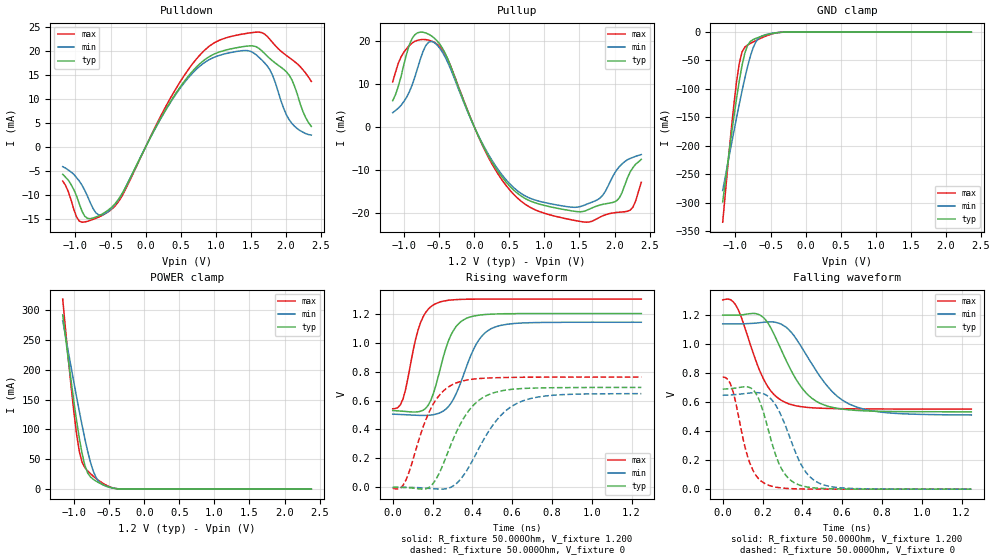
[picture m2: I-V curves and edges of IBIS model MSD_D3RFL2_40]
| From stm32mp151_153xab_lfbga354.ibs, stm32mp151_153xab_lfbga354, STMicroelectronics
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[Model] MSD_D3RFL2_40
Model_type   I/O
C_comp 2.255pF   2.172pF   2.373pF
Vinh = 820.000mV
Vinl = 380.000mV
Vmeas = 600.000mV
Vref = 600.000mV
[Model Spec]
Vinh   820.000mV   790.000mV   870.000mV
Vinl   380.000mV   350.000mV   430.000mV
Vmeas   600.000mV   570.000mV   650.000mV
Vref   600.000mV   570.000mV   650.000mV
[Temperature Range]   25.000   125.000   -40.000
[Voltage Range]   1.200V   1.140V   1.300V
[GND Clamp Reference]   0.00V   0.00V   0.00V
[Pulldown Reference]   0.00V   0.00V   0.00V
[POWER Clamp Reference]   1.200V   1.140V   1.300V
[Pullup Reference]   1.200V   1.140V   1.300V
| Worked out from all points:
|   slope of the pulldown table from 0 to 0.18 V, typ, clamps not added: 35.6 ohm
|   slope of the pullup table from 0 to 0.18 V, typ, clamps not added: 29.6 ohm
|   GND clamp passes 1 mA (typ) near -0.41 V on its own axis
|   POWER clamp passes 1 mA (typ) near -0.41 V on its own axis
|   rising waveform, R_fixture 50.000Ohm, V_fixture 1.200: 20-80 % time 90.2ps typ, 117ps min, 76.1ps max; typ from 0.531 V to 1.2 V
|   rising waveform, R_fixture 50.000Ohm, V_fixture 0: 20-80 % time 149ps typ, 181ps min, 126ps max; typ from 0.001 V to 0.69 V
|   falling waveform, R_fixture 50.000Ohm, V_fixture 1.200: 20-80 % time 159ps typ, 199ps min, 127ps max; typ from 1.2 V to 0.533 V
|   falling waveform, R_fixture 50.000Ohm, V_fixture 0: 20-80 % time 97.4ps typ, 122ps min, 82ps max; typ from 0.69 V to 0 V
[GND Clamp]
-1.182V   -298.7mA   -278.8mA   -334.6mA
-1.064V   -186.5mA   -201.2mA   -176.5mA
-984.9mV  -117.2mA   -151mA     -87.71mA
-945.5mV  -85.9mA    -126.8mA   -54.95mA
-906.1mV  -58.53mA   -103.4mA   -34.88mA
-866.7mV  -37.07mA   -81.25mA   -26.52mA
-827.3mV  -23.31mA   -60.73mA   -22.77mA
-748.5mV  -13.21mA   -27.8mA    -17.44mA
-709.1mV  -11.06mA   -17.22mA   -14.97mA
-630.3mV  -7.606mA   -7.312mA   -10.35mA
-472.7mV  -2.342mA   -2.056mA   -3.037mA
2.364V    24.05nA    406.6nA    2.606nA
[Power Clamp]
-1.164V   291.7mA    282.1mA    318.2mA
-1.085V   217.9mA    230.4mA    219.1mA
-1.006V   147.8mA    179.6mA    130.3mA
-966.7mV  115.3mA    154.7mA    92.57mA
-927.3mV  85.58mA    130.4mA    63.26mA
-887.9mV  59.89mA    107mA      45.2mA
-809.1mV  27.4mA     63.99mA    30.58mA
-730.3mV  16.7mA     30.88mA    21.97mA
-690.9mV  13.64mA    20.08mA    18.15mA
-572.7mV  6.466mA    6.412mA    8.539mA
-336.4mV  182.5uA    350.9uA    204.7uA
2.382V    -20.25nA   -432nA     -2.132nA
[Pulldown]
-1.182V   -5.7mA     -4.1mA     -7.1mA
-945.5mV  -11.88mA   -7.1mA     -15.47mA
-866.7mV  -14.47mA   -9.07mA    -15.65mA
-709.1mV  -14.63mA   -13.73mA   -14.9mA
-551.5mV  -13.38mA   -13.65mA   -13.72mA
-354.6mV  -10.22mA   -10.29mA   -10.71mA
590.9mV   14.46mA    14.13mA    15.79mA
945.5mV   19.18mA    18.53mA    21.44mA
1.379V    20.94mA    20.12mA    23.58mA
1.733V    19.01mA    16.97mA    23.14mA
2.009V    15.7mA     6.71mA     19.11mA
2.364V    4.3mA      2.5mA      13.7mA
[Pullup]
-1.164V   6.1mA      3.309mA    10.46mA
-887.9mV  20.5mA     9.694mA    19.46mA
-730.3mV  21.97mA    17.57mA    20.3mA
-612.1mV  21.14mA    19.84mA    19.93mA
-375.8mV  15.67mA    14.87mA    15.59mA
215.2mV   -7.105mA   -6.743mA   -7.481mA
727.3mV   -16.61mA   -16.01mA   -17.94mA
1.515V    -19.67mA   -18.45mA   -21.93mA
1.791V    -18.12mA   -16.51mA   -20.92mA
1.988V    -17.46mA   -11.09mA   -19.92mA
2.224V    -10.4mA    -7.295mA   -19.28mA
2.382V    -7.5mA     -6.395mA   -12.82mA
[Ramp]
R_load=50.000Ohm
dV/dt_r   407.310mV/120.000ps  383.549mV/149.500ps  452.790mV/101.000ps
dV/dt_f   407.310mV/129.000ps  383.519mV/161.500ps  452.790mV/104.500ps
[Rising waveform]
R_fixture=50.000Ohm
V_fixture=1.200
V_fixture_min=1.140
V_fixture_max=1.300
0s        530.6mV    505.9mV    542.7mV
52ps      525.8mV    502.7mV    612mV
141ps     526.3mV    497.2mV    1.141V
179ps     568.8mV    498mV      1.231V
217ps     705mV      506mV      1.269V
268ps     964.5mV    541.5mV    1.289V
319ps     1.112V     648mV      1.296V
421ps     1.186V     992mV      1.3V
498ps     1.196V     1.098V     1.3V
1.249ns   1.2V       1.14V      1.3V
[Rising waveform]
R_fixture=50.000Ohm
V_fixture=0
0s        873.9uV    858uV      -5.749mV
64ps      -93.44uV   771.7uV    43.92mV
192ps     10.23mV    -7.297mV   545.8mV
307ps     343.4mV    13.58mV    714mV
370ps     506.9mV    112.1mV    740.5mV
434ps     602.6mV    272.5mV    751.5mV
536ps     663.9mV    486.9mV    757.8mV
626ps     680.5mV    581.7mV    760.1mV
804ps     688.2mV    636.2mV    761.4mV
1.249ns   690.4mV    647.4mV    761.5mV
[Falling waveform]
R_fixture=50.000Ohm
V_fixture=1.200
V_fixture_min=1.140
V_fixture_max=1.300
0s        1.2V       1.139V     1.304V
77ps      1.2V       1.139V     1.24V
192ps     1.196V     1.148V     797.1mV
243ps     1.108V     1.153V     674.9mV
319ps     886.2mV    1.116V     595.2mV
447ps     627.5mV    865.2mV    561mV
549ps     564.3mV    674.1mV    555.7mV
638ps     546.3mV    584.9mV    553.8mV
817ps     535.9mV    527.8mV    552.4mV
1.249ns   533mV      511.1mV    552.2mV
[Falling waveform]
R_fixture=50.000Ohm
V_fixture=0
0s        689.8mV    647.5mV    772mV
52ps      694.5mV    650.5mV    672.5mV
141ps     697.6mV    663.3mV    162.9mV
179ps     628.4mV    664.7mV    74.16mV
217ps     470.3mV    650mV      34.96mV
268ps     227.2mV    574.9mV    13.54mV
319ps     92.19mV    423.2mV    5.501mV
396ps     23.82mV    164.3mV    1.426mV
485ps     6.144mV    40.92mV    291uV
1.249ns   1.494uV    17.97uV    0V
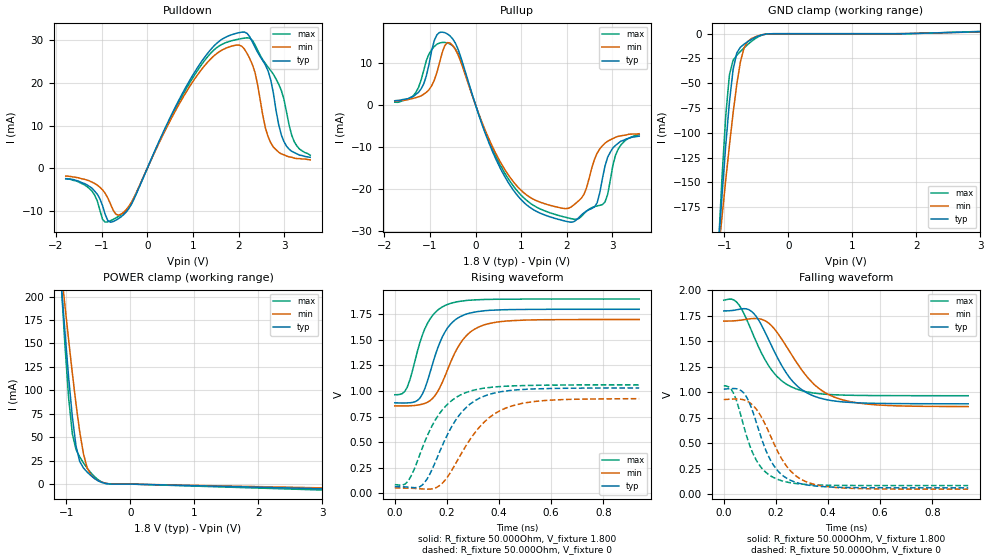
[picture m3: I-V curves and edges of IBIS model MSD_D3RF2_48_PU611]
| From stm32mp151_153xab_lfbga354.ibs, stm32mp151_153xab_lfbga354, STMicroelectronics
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[Model] MSD_D3RF2_48_PU611
Model_type   I/O
C_comp 2.420pF   2.338pF   2.542pF
Vinh = 1.150V
Vinl = 650.000mV
Vmeas = 900.000mV
Vref = 900.000mV
[Model Spec]
Vinh   1.150V   1.100V   1.200V
Vinl   650.000mV   600.000mV   700.000mV
Vmeas   900.000mV   850.000mV   950.000mV
Vref   900.000mV   850.000mV   950.000mV
[Temperature Range]   25.000   125.000   -40.000
[Voltage Range]   1.800V   1.700V   1.900V
[GND Clamp Reference]   0.00V   0.00V   0.00V
[Pulldown Reference]   0.00V   0.00V   0.00V
[POWER Clamp Reference]   1.800V   1.700V   1.900V
[Pullup Reference]   1.800V   1.700V   1.900V
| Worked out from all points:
|   slope of the pulldown table from 0 to 0.27 V, typ, clamps not added: 41 ohm
|   slope of the pullup table from 0 to 0.27 V, typ, clamps not added: 32.3 ohm
|   GND clamp passes 1 mA (typ) near -0.40 V on its own axis
|   POWER clamp passes 1 mA (typ) near -0.41 V on its own axis
|   rising waveform, R_fixture 50.000Ohm, V_fixture 1.800: 20-80 % time 80.9ps typ, 100ps min, 74.8ps max; typ from 0.885 V to 1.8 V
|   rising waveform, R_fixture 50.000Ohm, V_fixture 0: 20-80 % time 126ps typ, 149ps min, 119ps max; typ from 0.065 V to 1.03 V
|   falling waveform, R_fixture 50.000Ohm, V_fixture 1.800: 20-80 % time 126ps typ, 151ps min, 117ps max; typ from 1.8 V to 0.888 V
|   falling waveform, R_fixture 50.000Ohm, V_fixture 0: 20-80 % time 91.7ps typ, 112ps min, 83.3ps max; typ from 1.03 V to 0.064 V
[GND Clamp]
-1.785V   -902.7mA   -689.9mA   -1.212A
-1.094V   -215.4mA   -221.4mA   -216.2mA
-1.036V   -162.5mA   -184.1mA   -144.1mA
-978.8mV  -112.8mA   -147.7mA   -82.76mA
-921.2mV  -69mA      -112.8mA   -41.61mA
-863.6mV  -36.18mA   -79.97mA   -26.74mA
-806.1mV  -19.38mA   -50.93mA   -21.76mA
-748.5mV  -13.55mA   -28.08mA   -17.89mA
-690.9mV  -10.49mA   -14.02mA   -14.25mA
-575.8mV  -5.695mA   -4.879mA   -7.699mA
-287.9mV  -74.99uA   -123uA     -60.99uA
3.57V     2.964mA    2.553mA    3.541mA
[Power Clamp]
-1.77V    884.1mA    691.2mA    1.161A
-1.079V   213.1mA    227.1mA    213mA
-1.021V   161.6mA    189.9mA    147.5mA
-963.6mV  113.5mA    153.4mA    91.69mA
-906.1mV  71.69mA    118.2mA    53.58mA
-848.5mV  40.49mA    85.18mA    36.76mA
-790.9mV  24.18mA    55.77mA    28.99mA
-733.3mV  17.31mA    32.52mA    22.74mA
-618.2mV  9.175mA    9.93mA     12.21mA
-503mV    3.531mA    3.626mA    4.592mA
-330.3mV  169.7uA    350.8uA    198.1uA
3.585V    -5.947mA   -4.827mA   -7.552mA
[Pulldown]
-1.785V   -2.4mA     -1.8mA     -2.4mA
-1.209V   -4.6mA     -3.2mA     -5.3mA
-921.2mV  -10.71mA   -5.8mA     -12.53mA
-690.9mV  -12.11mA   -10.65mA   -11.59mA
-518.2mV  -10.81mA   -10.23mA   -10.36mA
1.094V    23.43mA    21.74mA    22.76mA
2.073V    31.84mA    28.54mA    30.34mA
2.361V    28.33mA    22.42mA    28.91mA
2.706V    20.69mA    6mA        22.85mA
2.994V    6.3mA      3.2mA      16.2mA
3.224V    3.7mA      2.4mA      6.2mA
3.57V     2.6mA      2mA        3.1mA
[Pullup]
-1.77V    1mA        973.7uA    673.7uA
-1.309V   2.5mA      1.747mA    2.963mA
-1.021V   9.6mA      3.616mA    12.09mA
-848.5mV  16.65mA    7.666mA    14.42mA
-618.2mV  16.89mA    14.82mA    14.74mA
763.6mV   -19.21mA   -17.32mA   -18.28mA
2.088V    -27.84mA   -24.27mA   -26.98mA
2.376V    -25.6mA    -21.22mA   -25.8mA
2.606V    -24.21mA   -12.89mA   -24.14mA
2.779V    -17.5mA    -9.684mA   -23.66mA
3.124V    -9.1mA     -7.453mA   -10.51mA
3.585V    -7.4mA     -6.826mA   -7.047mA
[Ramp]
R_load=50.000Ohm
dV/dt_r   563.493mV/104.500ps  514.551mV/125.500ps  571.944mV/97.000ps
dV/dt_f   563.493mV/109.000ps  514.551mV/132.000ps  571.944mV/101.000ps
[Rising waveform]
R_fixture=50.000Ohm
V_fixture=1.800
V_fixture_min=1.700
V_fixture_max=1.900
0s        884.7mV    855.2mV    963.7mV
29ps      883.2mV    854.3mV    975.4mV
48ps      883.7mV    854.9mV    1.039V
96ps      929.5mV    866.1mV    1.471V
115ps     1.022V     879.1mV    1.607V
154ps     1.34V      954.3mV    1.766V
202ps     1.616V     1.205V     1.847V
269ps     1.748V     1.526V     1.884V
355ps     1.788V     1.656V     1.896V
938ps     1.8V       1.7V       1.9V
[Rising waveform]
R_fixture=50.000Ohm
V_fixture=0
0s        64.78mV    51.61mV    84.22mV
48ps      60.37mV    49.89mV    109.8mV
115ps     106.3mV    40.91mV    503.3mV
183ps     469.6mV    99.37mV    817.2mV
230ps     700.8mV    273.6mV    928.3mV
269ps     826.1mV    446.7mV    981.2mV
355ps     960.8mV    723.1mV    1.032V
451ps     1.008V     855.2mV    1.05V
614ps     1.026V     913.1mV    1.058V
938ps     1.03V      925.2mV    1.06V
[Falling waveform]
R_fixture=50.000Ohm
V_fixture=1.800
V_fixture_min=1.700
V_fixture_max=1.900
0s        1.799V     1.699V     1.904V
29ps      1.802V     1.7V       1.915V
58ps      1.814V     1.706V     1.859V
115ps     1.774V     1.724V     1.552V
154ps     1.613V     1.708V     1.34V
192ps     1.411V     1.629V     1.192V
278ps     1.072V     1.299V     1.034V
365ps     946.9mV    1.039V     987.7mV
460ps     906mV      924.2mV    973.4mV
938ps     888.1mV    861.2mV    967.4mV
[Falling waveform]
R_fixture=50.000Ohm
V_fixture=0
0s        1.032V     929.8mV    1.065V
20ps      1.036V     932.8mV    1.052V
39ps      1.038V     935.1mV    983.9mV
87ps      956.2mV    917.7mV    576.4mV
135ps     623.7mV    798.6mV    293.2mV
163ps     422.7mV    665.5mV    212.8mV
202ps     247.6mV    445.9mV    152.4mV
259ps     135mV      222.4mV    112.9mV
355ps     81.42mV    93.96mV    92.49mV
938ps     64.28mV    51.3mV     86.62mV
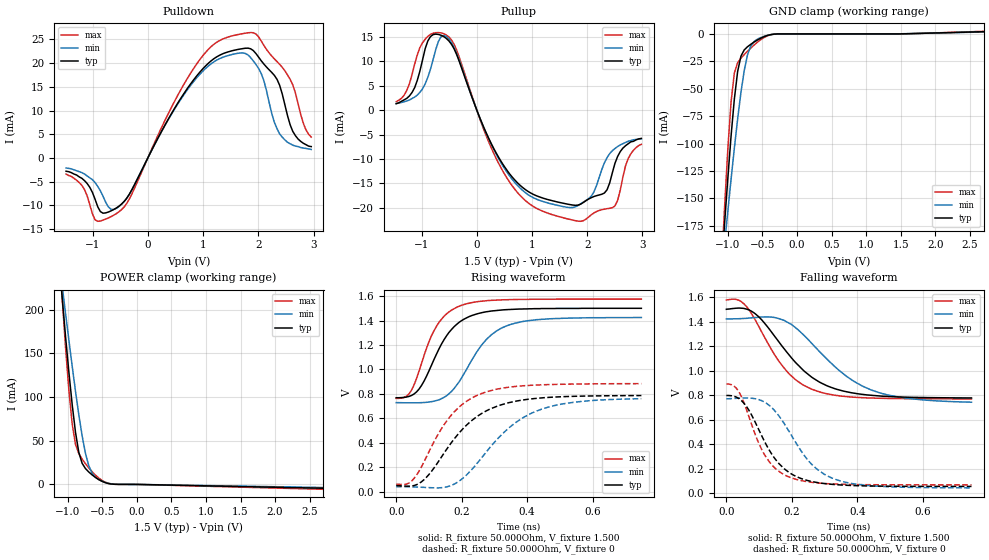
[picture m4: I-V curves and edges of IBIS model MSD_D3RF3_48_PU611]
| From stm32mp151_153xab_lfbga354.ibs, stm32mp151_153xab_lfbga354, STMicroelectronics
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[Model] MSD_D3RF3_48_PU611
Model_type   I/O
C_comp 2.434pF   2.351pF   2.557pF
Vinh = 925.000mV
Vinl = 575.000mV
Vmeas = 750.000mV
Vref = 750.000mV
[Model Spec]
Vinh   925.000mV   888.000mV   963.000mV
Vinl   575.000mV   538.000mV   613.000mV
Vmeas   750.000mV   713.000mV   788.000mV
Vref   750.000mV   713.000mV   788.000mV
[Temperature Range]   25.000   125.000   -40.000
[Voltage Range]   1.500V   1.425V   1.575V
[GND Clamp Reference]   0.00V   0.00V   0.00V
[Pulldown Reference]   0.00V   0.00V   0.00V
[POWER Clamp Reference]   1.500V   1.425V   1.575V
[Pullup Reference]   1.500V   1.425V   1.575V
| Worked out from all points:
|   slope of the pulldown table from 0 to 0.225 V, typ, clamps not added: 44.1 ohm
|   slope of the pullup table from 0 to 0.225 V, typ, clamps not added: 37.5 ohm
|   GND clamp passes 1 mA (typ) near -0.40 V on its own axis
|   POWER clamp passes 1 mA (typ) near -0.41 V on its own axis
|   rising waveform, R_fixture 50.000Ohm, V_fixture 1.500: 20-80 % time 91.6ps typ, 108ps min, 76.8ps max; typ from 0.769 V to 1.5 V
|   rising waveform, R_fixture 50.000Ohm, V_fixture 0: 20-80 % time 144ps typ, 163ps min, 123ps max; typ from 0.051 V to 0.787 V
|   falling waveform, R_fixture 50.000Ohm, V_fixture 1.500: 20-80 % time 149ps typ, 175ps min, 121ps max; typ from 1.5 V to 0.778 V
|   falling waveform, R_fixture 50.000Ohm, V_fixture 0: 20-80 % time 100ps typ, 118ps min, 83.1ps max; typ from 0.798 V to 0.055 V
[GND Clamp]
-1.48V    -595mA     -480.6mA   -764.6mA
-1.098V   -218.9mA   -223.9mA   -221.2mA
-1.05V    -174.8mA   -192.9mA   -160.5mA
-1.002V   -132.5mA   -162.4mA   -106.1mA
-954.6mV  -93.38mA   -132.8mA   -62.24mA
-906.8mV  -59.5mA    -104.2mA   -35.79mA
-859.1mV  -34.24mA   -77.51mA   -26.21mA
-811.4mV  -20.29mA   -53.38mA   -22.14mA
-715.9mV  -11.7mA    -18.98mA   -15.79mA
-572.7mV  -5.58mA    -4.768mA   -7.539mA
-286.4mV  -69.81uA   -117.8uA   -56.41uA
2.959V    2.404mA    2.05mA     2.9mA
[Power Clamp]
-1.459V   578.8mA    480.2mA    724.4mA
-1.077V   211.7mA    226.1mA    211.2mA
-1.03V    168.8mA    195.2mA    156.4mA
-981.8mV  128.2mA    164.8mA    107.5mA
-934.1mV  91.06mA    135.1mA    68.98mA
-886.4mV  59.53mA    106.6mA    45.83mA
-838.6mV  36.63mA    79.81mA    35.19mA
-743.2mV  18.22mA    35.86mA    23.75mA
-647.7mV  11mA       13.06mA    14.65mA
-552.3mV  5.639mA    5.582mA    7.423mA
-313.6mV  109.4uA    249.9uA    123.7uA
2.98V     -4.843mA   -3.907mA   -6.18mA
[Pulldown]
-1.48V    -2.8mA     -2.1mA     -3.4mA
-1.193V   -4.3mA     -3.1mA     -5.8mA
-954.6mV  -8.73mA    -5.2mA     -13.05mA
-811.4mV  -11.65mA   -8.07mA    -13.11mA
-525mV    -10.19mA   -10.28mA   -11.37mA
906.8mV   17.61mA    17.2mA     20.19mA
1.766V    23.14mA    22.04mA    26.32mA
2.052V    20.52mA    17.86mA    24.7mA
2.386V    15.36mA    5.1mA      19.76mA
2.625V    5.6mA      2.7mA      15.4mA
2.816V    3.1mA      2.1mA      7.3mA
2.959V    2.4mA      1.8mA      4.4mA
[Pullup]
-1.459V   1.3mA      1.357mA    1.729mA
-1.173V   3.6mA      2.371mA    7.243mA
-981.8mV  10.3mA     4.357mA    13.82mA
-838.6mV  15.06mA    8.371mA    15.51mA
-552.3mV  14.69mA    15.08mA    15.38mA
640.9mV   -13.72mA   -14.19mA   -15.51mA
1.834V    -19.47mA   -19.55mA   -22.76mA
2.12V     -17.71mA   -16.78mA   -21.08mA
2.311V    -16.99mA   -10.81mA   -20.29mA
2.502V    -10.9mA    -7.871mA   -19.63mA
2.741V    -6.9mA     -6.386mA   -9.928mA
2.98V     -5.8mA     -5.9mA     -7.014mA
[Ramp]
R_load=50.000Ohm
dV/dt_r   437.283mV/118.500ps  423.876mV/137.000ps  486.861mV/101.000ps
dV/dt_f   437.283mV/125.000ps  423.846mV/149.000ps  486.861mV/103.000ps
[Rising waveform]
R_fixture=50.000Ohm
V_fixture=1.500
V_fixture_min=1.425
V_fixture_max=1.575
0s        769mV      729.4mV    763.4mV
39ps      779.7mV    727.4mV    800.5mV
69ps      837.3mV    728mV      980.1mV
100ps     987.8mV    734.3mV    1.226V
123ps     1.125V     746.4mV    1.353V
154ps     1.276V     785.1mV    1.455V
192ps     1.385V     898.2mV    1.517V
276ps     1.472V     1.247V     1.562V
345ps     1.49V      1.364V     1.571V
749ps     1.5V       1.425V     1.575V
[Rising waveform]
R_fixture=50.000Ohm
V_fixture=0
0s        51.41mV    42.64mV    63.72mV
46ps      47.29mV    40.53mV    85.37mV
85ps      99.46mV    36.41mV    245mV
131ps     255.4mV    32.43mV    484mV
169ps     403.7mV    52.98mV    629.1mV
253ps     626.5mV    251.9mV    795.4mV
345ps     729.3mV    524mV      855.6mV
444ps     767.6mV    675.6mV    874.6mV
544ps     780.7mV    732.6mV    880.8mV
749ps     786.9mV    760.9mV    884.4mV
[Falling waveform]
R_fixture=50.000Ohm
V_fixture=1.500
V_fixture_min=1.425
V_fixture_max=1.575
0s        1.503V     1.424V     1.579V
46ps      1.512V     1.427V     1.565V
85ps      1.473V     1.435V     1.432V
138ps     1.317V     1.439V     1.173V
184ps     1.155V     1.401V     998.3mV
261ps     947.4mV    1.224V     849.7mV
368ps     828.3mV    953.4mV    788.7mV
444ps     799.6mV    842.1mV    777.2mV
552ps     784.3mV    775.3mV    772.2mV
749ps     778.1mV    743.4mV    770.3mV
[Falling waveform]
R_fixture=50.000Ohm
V_fixture=0
0s        798.3mV    770.5mV    892mV
39ps      772.3mV    776.3mV    825.3mV
69ps      677.4mV    777.6mV    625.8mV
115ps     431.1mV    746.4mV    321.7mV
154ps     262.6mV    654.2mV    191.7mV
192ps     168.4mV    502.9mV    131.5mV
261ps     94.89mV    235.1mV    88.27mV
337ps     68.77mV    108.8mV    73.69mV
467ps     57.1mV     55.89mV    68.26mV
749ps     54.62mV    42.96mV    67.42mV
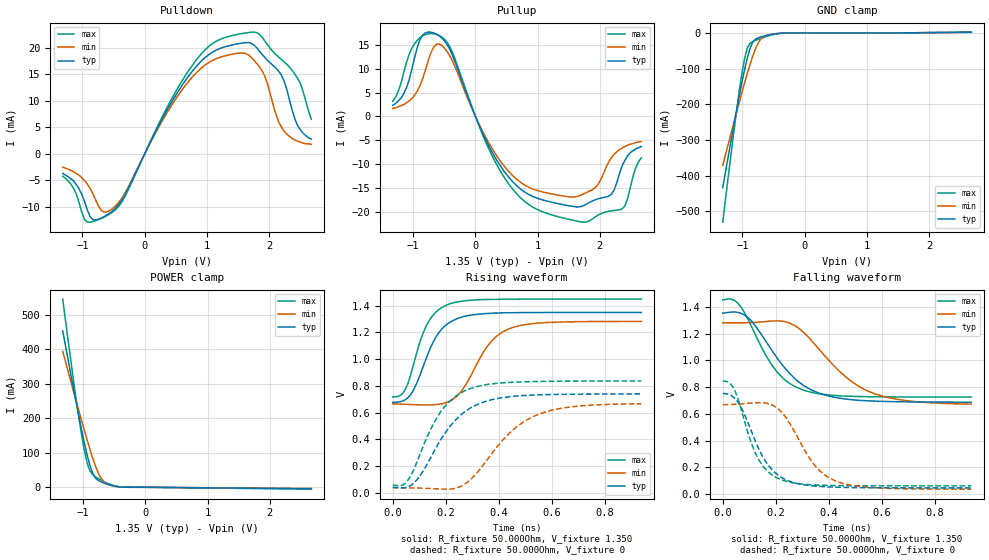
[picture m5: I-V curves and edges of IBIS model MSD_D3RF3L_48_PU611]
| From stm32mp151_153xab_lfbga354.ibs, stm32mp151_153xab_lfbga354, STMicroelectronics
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[Model] MSD_D3RF3L_48_PU611
Model_type   I/O
C_comp 2.442pF   2.357pF   2.567pF
Vinh = 810.000mV
Vinl = 540.000mV
Vmeas = 675.000mV
Vref = 675.000mV
[Model Spec]
Vinh   810.000mV   777.000mV   860.000mV
Vinl   540.000mV   507.000mV   590.000mV
Vmeas   675.000mV   642.000mV   725.000mV
Vref   675.000mV   642.000mV   725.000mV
[Temperature Range]   25.000   125.000   -40.000
[Voltage Range]   1.350V   1.283V   1.450V
[GND Clamp Reference]   0.00V   0.00V   0.00V
[Pulldown Reference]   0.00V   0.00V   0.00V
[POWER Clamp Reference]   1.350V   1.283V   1.450V
[Pullup Reference]   1.350V   1.283V   1.450V
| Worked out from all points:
|   slope of the pulldown table from 0 to 0.203 V, typ, clamps not added: 42.2 ohm
|   slope of the pullup table from 0 to 0.203 V, typ, clamps not added: 34.5 ohm
|   GND clamp passes 1 mA (typ) near -0.40 V on its own axis
|   POWER clamp passes 1 mA (typ) near -0.41 V on its own axis
|   rising waveform, R_fixture 50.000Ohm, V_fixture 1.350: 20-80 % time 92.2ps typ, 115ps min, 77.8ps max; typ from 0.677 V to 1.35 V
|   rising waveform, R_fixture 50.000Ohm, V_fixture 0: 20-80 % time 147ps typ, 178ps min, 125ps max; typ from 0.043 V to 0.741 V
|   falling waveform, R_fixture 50.000Ohm, V_fixture 1.350: 20-80 % time 163ps typ, 195ps min, 130ps max; typ from 1.35 V to 0.688 V
|   falling waveform, R_fixture 50.000Ohm, V_fixture 0: 20-80 % time 105ps typ, 124ps min, 87.4ps max; typ from 0.753 V to 0.047 V
[GND Clamp]
-1.318V   -433.7mA   -371.1mA   -530mA
-1.142V   -261.4mA   -253.3mA   -281.2mA
-1.055V   -178.9mA   -195.8mA   -166mA
-1.011V   -139.7mA   -167.7mA   -114.9mA
-966.7mV  -102.9mA   -140.2mA   -71.99mA
-922.7mV  -70.02mA   -113.6mA   -42.32mA
-878.8mV  -43.37mA   -88.29mA   -28.9mA
-790.9mV  -17.22mA   -44.18mA   -20.7mA
-703mV    -11.06mA   -16.21mA   -14.99mA
-527.3mV  -4.011mA   -3.391mA   -5.355mA
-307.6mV  -127.4uA   -187.4uA   -115uA
2.68V     2.164mA    1.839mA    2.56mA
[Power Clamp]
-1.33V    453.1mA    393.6mA    545.2mA
-1.111V   242.6mA    247.9mA    251.6mA
-1.023V   162.8mA    190.9mA    148.7mA
-978.8mV  125.7mA    162.9mA    104.2mA
-934.9mV  91.62mA    135.6mA    68.68mA
-890.9mV  62.22mA    109.2mA    47.04mA
-847mV    39.86mA    84.29mA    36.52mA
-803mV    26.49mA    61.46mA    30.42mA
-715.1mV  15.8mA     26.67mA    20.89mA
-671.2mV  12.56mA    16.56mA    16.71mA
-407.6mV  931.1uA    1.216mA    1.127mA
2.668V    -4.266mA   -3.419mA   -5.488mA
[Pulldown]
-1.318V   -3.7mA     -2.5mA     -4.2mA
-1.098V   -5.8mA     -3.7mA     -7.6mA
-922.7mV  -10.54mA   -5.7mA     -12.83mA
-703mV    -12.11mA   -10.54mA   -12.17mA
-483.3mV  -10.4mA    -9.969mA   -10.65mA
790.9mV   15.91mA    14.77mA    17.06mA
1.582V    20.87mA    18.98mA    22.68mA
1.889V    18.72mA    15.63mA    21.96mA
2.197V    14.84mA    5.1mA      17.77mA
2.329V    10.1mA     3.3mA      16.32mA
2.461V    5.3mA      2.4mA      14.2mA
2.68V     2.8mA      1.8mA      6.5mA
[Pullup]
-1.33V    2.3mA      1.652mA    3.135mA
-1.023V   9.8mA      3.715mA    14.27mA
-890.9mV  16.11mA    6.472mA    16.51mA
-715.1mV  17.65mA    13.35mA    17.35mA
-451.5mV  14.98mA    13.53mA    15.46mA
295.4mV   -8.126mA   -7.329mA   -8.964mA
910.6mV   -16.72mA   -15.17mA   -18.95mA
1.702V    -18.93mA   -16.49mA   -22.14mA
1.965V    -17.33mA   -14.42mA   -20.77mA
2.185V    -16.37mA   -8.694mA   -19.82mA
2.361V    -10.3mA    -6.643mA   -19.39mA
2.668V    -6.3mA     -5.3mA     -8.693mA
[Ramp]
R_load=50.000Ohm
dV/dt_r   407.025mV/120.000ps  374.118mV/149.000ps  449.694mV/102.000ps
dV/dt_f   407.025mV/134.500ps  374.058mV/162.000ps  449.694mV/109.000ps
[Rising waveform]
R_fixture=50.000Ohm
V_fixture=1.350
V_fixture_min=1.283
V_fixture_max=1.450
0s        677.4mV    665.9mV    718.5mV
39ps      688.6mV    663.4mV    747.5mV
68ps      736.1mV    661.2mV    884.2mV
125ps     999.5mV    658.2mV    1.243V
163ps     1.165V     660.9mV    1.353V
202ps     1.257V     675.6mV    1.404V
259ps     1.314V     760.6mV    1.434V
365ps     1.343V     1.117V     1.447V
432ps     1.347V     1.222V     1.449V
938ps     1.35V      1.283V     1.45V
[Rising waveform]
R_fixture=50.000Ohm
V_fixture=0
0s        42.68mV    37.92mV    58.75mV
48ps      40.35mV    37.89mV    72.84mV
87ps      88.5mV     37.09mV    208.7mV
135ps     233.2mV    34.13mV    441.6mV
183ps     403.7mV    29.26mV    612.1mV
278ps     615.8mV    74.7mV     768.8mV
441ps     719.8mV    448.8mV    826.8mV
527ps     731.9mV    568.3mV    832.8mV
662ps     738mV      641.1mV    836.3mV
938ps     740.7mV    667.3mV    837.3mV
[Falling waveform]
R_fixture=50.000Ohm
V_fixture=1.350
V_fixture_min=1.283
V_fixture_max=1.450
0s        1.354V     1.282V     1.453V
48ps      1.362V     1.282V     1.444V
96ps      1.319V     1.283V     1.306V
154ps     1.17V      1.289V     1.07V
202ps     1.028V     1.296V     922.4mV
298ps     823.3mV    1.223V     782.9mV
441ps     718.1mV    917.7mV    735.6mV
547ps     698.4mV    771.9mV    729.2mV
700ps     690.3mV    698.1mV    726.9mV
938ps     687.9mV    673.5mV    726.2mV
[Falling waveform]
R_fixture=50.000Ohm
V_fixture=0
0s        752.5mV    669.9mV    845mV
29ps      741.6mV    671.2mV    826.5mV
48ps      712.2mV    672.8mV    764.3mV
106ps     481.8mV    681.1mV    393.7mV
135ps     343.7mV    684.1mV    261.3mV
211ps     139.6mV    635.2mV    116.5mV
345ps     61.28mV    221.5mV    69.32mV
422ps     52.48mV    102.2mV    64.68mV
566ps     48.02mV    49.22mV    62.96mV
938ps     47.18mV    37.63mV    62.61mV
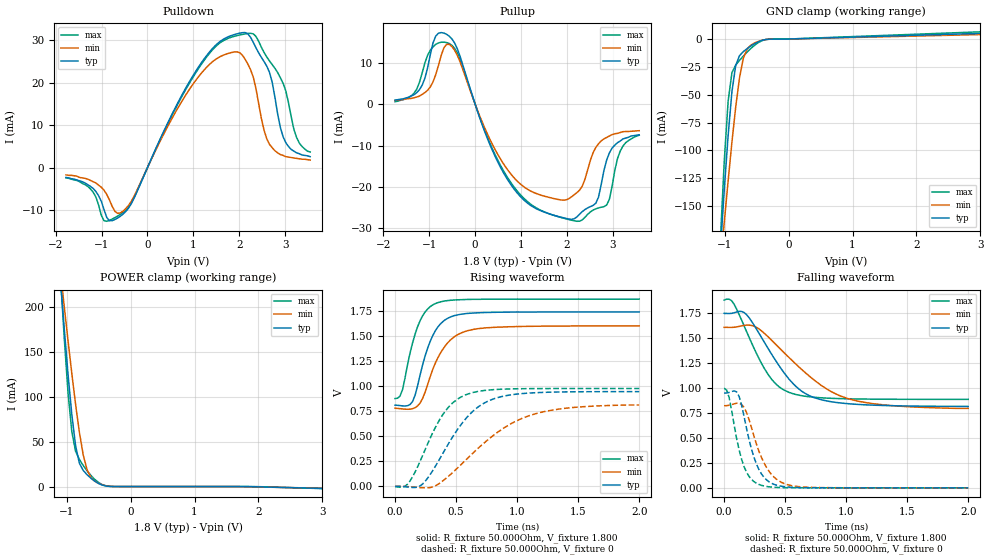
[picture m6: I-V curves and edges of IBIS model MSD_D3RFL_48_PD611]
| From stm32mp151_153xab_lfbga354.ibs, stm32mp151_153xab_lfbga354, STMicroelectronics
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[Model] MSD_D3RFL_48_PD611
Model_type   I/O
C_comp 2.419pF   2.335pF   2.543pF
Vinh = 1.440V
Vinl = 360.000mV
Vmeas = 900.000mV
Vref = 900.000mV
[Model Spec]
Vinh   1.440V   1.365V   1.515V
Vinl   360.000mV   285.000mV   435.000mV
Vmeas   900.000mV   825.000mV   975.000mV
Vref   900.000mV   825.000mV   975.000mV
[Temperature Range]   25.000   125.000   -40.000
[Voltage Range]   1.800V   1.650V   1.950V
[GND Clamp Reference]   0.00V   0.00V   0.00V
[Pulldown Reference]   0.00V   0.00V   0.00V
[POWER Clamp Reference]   1.800V   1.650V   1.950V
[Pullup Reference]   1.800V   1.650V   1.950V
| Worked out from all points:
|   slope of the pulldown table from 0 to 0.27 V, typ, clamps not added: 41 ohm
|   slope of the pullup table from 0 to 0.27 V, typ, clamps not added: 32.3 ohm
|   GND clamp passes 1 mA (typ) near -0.40 V on its own axis
|   POWER clamp passes 1 mA (typ) near -0.41 V on its own axis
|   rising waveform, R_fixture 50.000Ohm, V_fixture 1.800: 20-80 % time 148ps typ, 188ps min, 132ps max; typ from 0.813 V to 1.75 V
|   rising waveform, R_fixture 50.000Ohm, V_fixture 0: 20-80 % time 320ps typ, 495ps min, 248ps max; typ from 0.001 V to 0.948 V
|   falling waveform, R_fixture 50.000Ohm, V_fixture 1.800: 20-80 % time 322ps typ, 470ps min, 248ps max; typ from 1.75 V to 0.814 V
|   falling waveform, R_fixture 50.000Ohm, V_fixture 0: 20-80 % time 127ps typ, 158ps min, 110ps max; typ from 0.947 V to 0 V
[GND Clamp]
-1.773V   -890.5mA   -681.7mA   -1.194A
-1.064V   -187.2mA   -201.7mA   -177.4mA
-1.005V   -134.5mA   -163.9mA   -108.4mA
-945.5mV  -86.45mA   -127.3mA   -55.67mA
-886.4mV  -47.42mA   -92.59mA   -30.32mA
-827.3mV  -23.74mA   -61.09mA   -23.33mA
-768.2mV  -14.98mA   -35.02mA   -19.18mA
-709.1mV  -11.37mA   -17.47mA   -15.38mA
-650mV    -8.667mA   -9.004mA   -11.8mA
-531.8mV  -4.168mA   -3.528mA   -5.57mA
-295.4mV  -94.96uA   -150.6uA   -80.9uA
3.545V    5.967mA    4.73mA     7.643mA
[Power Clamp]
-1.745V   860.1mA    674.5mA    1.127A
-1.095V   228.4mA    237.9mA    233.3mA
-1.036V   174.8mA    199.6mA    164.2mA
-977.3mV  124.4mA    162mA      104mA
-918.2mV  79.78mA    125.5mA    60.72mA
-859.1mV  45.15mA    91.12mA    39.2mA
-800mV    25.86mA    60.27mA    30.1mA
-740.9mV  17.99mA    35.42mA    23.53mA
-681.8mV  13.28mA    19.02mA    17.73mA
-504.5mV  3.581mA    3.685mA    4.694mA
-268.2mV  27.02uA    97.66uA    31.41uA
3.573V    -3.02mA    -2.625mA   -3.524mA
[Pulldown]
-1.773V   -2.3mA     -1.7mA     -2.4mA
-1.241V   -4.4mA     -3mA       -5mA
-945.5mV  -9.88mA    -5.3mA     -12.48mA
-531.8mV  -10.94mA   -10.24mA   -10.54mA
1.064V    22.92mA    20.76mA    22.58mA
1.595V    29.86mA    26.24mA    29.55mA
2.068V    31.83mA    26.53mA    31.41mA
2.305V    29.56mA    21.37mA    31.55mA
2.659V    22.45mA    5.5mA      25.16mA
3.014V    5.9mA      2.6mA      18.1mA
3.25V     3.5mA      2.2mA      7.1mA
3.545V    2.6mA      1.8mA      3.7mA
[Pullup]
-1.745V   1mA        900uA      600uA
-1.332V   2.3mA      1.562mA    2.669mA
-1.036V   8.8mA      3.377mA    11.85mA
-859.1mV  16.48mA    7.15mA     14.48mA
-622.7mV  16.92mA    14.48mA    14.91mA
-386.4mV  13.35mA    11.77mA    12.34mA
795.5mV   -19.73mA   -17.13mA   -19.24mA
2.214V    -27.27mA   -21.39mA   -28.32mA
2.745V    -19.44mA   -8.877mA   -24.91mA
2.982V    -10.6mA    -7.338mA   -19.91mA
3.159V    -8.9mA     -6.838mA   -11.35mA
3.573V    -7.4mA     -6.4mA     -7.508mA
[Ramp]
R_load=50.000Ohm
dV/dt_r   564.000mV/234.500ps  490.979mV/343.000ps  590.250mV/189.500ps
dV/dt_f   563.968mV/225.000ps  490.014mV/315.000ps  590.250mV/179.000ps
[Rising waveform]
R_fixture=50.000Ohm
V_fixture=1.800
V_fixture_min=1.650
V_fixture_max=1.950
0s        813.2mV    782mV      878.5mV
41ps      808.5mV    777.6mV    904.3mV
62ps      805.5mV    774.9mV    970.9mV
143ps     848mV      777.3mV    1.433V
225ps     1.212V     878.4mV    1.705V
266ps     1.379V     1.016V     1.773V
327ps     1.55V      1.225V     1.827V
470ps     1.702V     1.482V     1.863V
654ps     1.735V     1.573V     1.871V
2ns       1.745V     1.606V     1.873V
[Rising waveform]
R_fixture=50.000Ohm
V_fixture=0
0s        1.048mV    1.221mV    -2.543mV
103ps     -5.794mV   -1.842mV   23.8mV
225ps     23.65mV    -13.02mV   307.5mV
388ps     323.2mV    52.22mV    712.6mV
470ps     491.9mV    137.1mV    833.8mV
572ps     666.4mV    255.5mV    913.1mV
776ps     860.9mV    482.3mV    965mV
1.103ns   934mV      709.4mV    978.1mV
1.43ns    946.1mV    786.3mV    979.3mV
2ns       948.2mV    814.3mV    979.5mV
[Falling waveform]
R_fixture=50.000Ohm
V_fixture=1.800
V_fixture_min=1.650
V_fixture_max=1.950
0s        1.745V     1.605V     1.877V
62ps      1.745V     1.604V     1.871V
184ps     1.732V     1.627V     1.563V
266ps     1.586V     1.604V     1.343V
368ps     1.379V     1.502V     1.121V
531ps     1.088V     1.304V     955.4mV
736ps     902.8mV    1.08V      906mV
1.021ns   841mV      889.6mV    890.3mV
1.369ns   821.6mV    822.9mV    885.8mV
2ns       814.2mV    794.7mV    884.7mV
[Falling waveform]
R_fixture=50.000Ohm
V_fixture=0
0s        947.4mV    820.9mV    994.2mV
41ps      953.7mV    825.8mV    906.1mV
82ps      969.6mV    839.8mV    631.1mV
123ps     914.5mV    846.4mV    380mV
184ps     593.7mV    753.3mV    156.8mV
225ps     385.7mV    600.3mV    84.37mV
286ps     182.1mV    364.5mV    33.83mV
409ps     35.12mV    107.6mV    5.968mV
572ps     5mV        18.24mV    979.5uV
2ns       15.56uV    91uV       0V
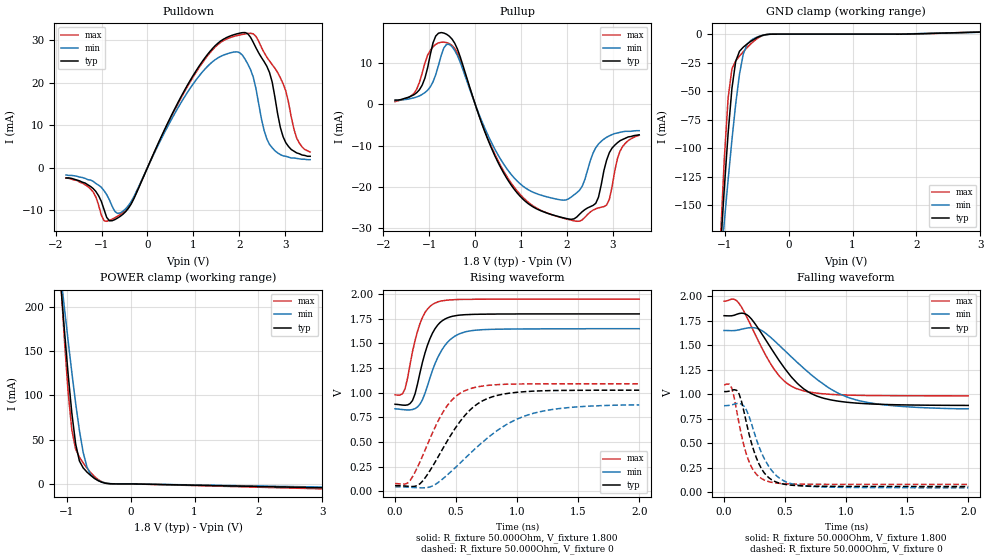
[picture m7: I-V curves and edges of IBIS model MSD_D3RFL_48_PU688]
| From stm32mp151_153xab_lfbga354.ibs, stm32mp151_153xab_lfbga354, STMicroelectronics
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[Model] MSD_D3RFL_48_PU688
Model_type   I/O
C_comp 2.432pF   2.348pF   2.557pF
Vinh = 1.440V
Vinl = 360.000mV
Vmeas = 900.000mV
Vref = 900.000mV
[Model Spec]
Vinh   1.440V   1.365V   1.515V
Vinl   360.000mV   285.000mV   435.000mV
Vmeas   900.000mV   825.000mV   975.000mV
Vref   900.000mV   825.000mV   975.000mV
[Temperature Range]   25.000   125.000   -40.000
[Voltage Range]   1.800V   1.650V   1.950V
[GND Clamp Reference]   0.00V   0.00V   0.00V
[Pulldown Reference]   0.00V   0.00V   0.00V
[POWER Clamp Reference]   1.800V   1.650V   1.950V
[Pullup Reference]   1.800V   1.650V   1.950V
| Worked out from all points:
|   slope of the pulldown table from 0 to 0.27 V, typ, clamps not added: 41 ohm
|   slope of the pullup table from 0 to 0.27 V, typ, clamps not added: 32.3 ohm
|   GND clamp passes 1 mA (typ) near -0.40 V on its own axis
|   POWER clamp passes 1 mA (typ) near -0.41 V on its own axis
|   rising waveform, R_fixture 50.000Ohm, V_fixture 1.800: 20-80 % time 132ps typ, 166ps min, 115ps max; typ from 0.883 V to 1.8 V
|   rising waveform, R_fixture 50.000Ohm, V_fixture 0: 20-80 % time 314ps typ, 494ps min, 243ps max; typ from 0.058 V to 1.03 V
|   falling waveform, R_fixture 50.000Ohm, V_fixture 1.800: 20-80 % time 331ps typ, 474ps min, 261ps max; typ from 1.8 V to 0.885 V
|   falling waveform, R_fixture 50.000Ohm, V_fixture 0: 20-80 % time 141ps typ, 176ps min, 121ps max; typ from 1.03 V to 0.057 V
[GND Clamp]
-1.773V   -890.6mA   -681.8mA   -1.194A
-1.064V   -187.3mA   -201.8mA   -177.4mA
-1.005V   -134.6mA   -163.9mA   -108.6mA
-945.5mV  -86.51mA   -127.3mA   -55.76mA
-886.4mV  -47.48mA   -92.62mA   -30.4mA
-827.3mV  -23.79mA   -61.12mA   -23.4mA
-768.2mV  -15.03mA   -35.05mA   -19.24mA
-709.1mV  -11.4mA    -17.49mA   -15.43mA
-650mV    -8.699mA   -9.023mA   -11.84mA
-531.8mV  -4.183mA   -3.537mA   -5.597mA
-295.4mV  -92.01uA   -148uA     -79.22uA
3.545V    2.598mA    2.292mA    3.012mA
[Power Clamp]
-1.745V   860.4mA    674.8mA    1.127A
-1.095V   228.6mA    238mA      233.4mA
-1.036V   175mA      199.7mA    164.4mA
-977.3mV  124.5mA    162.1mA    104.1mA
-918.2mV  79.87mA    125.7mA    60.84mA
-859.1mV  45.23mA    91.22mA    39.3mA
-800mV    25.93mA    60.35mA    30.19mA
-740.9mV  18.05mA    35.49mA    23.61mA
-681.8mV  13.34mA    19.08mA    17.79mA
-504.5mV  3.605mA    3.714mA    4.722mA
-268.2mV  29.8uA     103.3uA    33.46uA
3.573V    -5.274mA   -4.255mA   -6.708mA
[Pulldown]
-1.773V   -2.4mA     -1.7mA     -2.4mA
-1.182V   -4.9mA     -3.2mA     -5.7mA
-945.5mV  -9.83mA    -5.4mA     -12.48mA
-531.8mV  -10.94mA   -10.24mA   -10.53mA
1.064V    22.92mA    20.76mA    22.57mA
1.595V    29.86mA    26.25mA    29.55mA
2.068V    31.83mA    26.53mA    31.42mA
2.305V    29.55mA    21.36mA    31.55mA
2.659V    22.45mA    5.5mA      25.16mA
3.014V    5.9mA      2.7mA      18.1mA
3.25V     3.5mA      2.2mA      7mA
3.545V    2.7mA      1.9mA      3.7mA
[Pullup]
-1.745V   1mA        900uA      646.2uA
-1.332V   2.3mA      1.554mA    2.623mA
-1.036V   8.8mA      3.377mA    11.85mA
-859.1mV  16.48mA    7.15mA     14.48mA
-622.7mV  16.92mA    14.48mA    14.91mA
-386.4mV  13.34mA    11.77mA    12.34mA
795.5mV   -19.73mA   -17.12mA   -19.24mA
2.214V    -27.27mA   -21.4mA    -28.31mA
2.686V    -22.48mA   -9.623mA   -25.08mA
2.982V    -10.6mA    -7.338mA   -19.95mA
3.159V    -8.8mA     -6.792mA   -11.25mA
3.573V    -7.4mA     -6.4mA     -7.508mA
[Ramp]
R_load=50.000Ohm
dV/dt_r   565.665mV/224.000ps  493.119mV/331.000ps  593.802mV/180.000ps
dV/dt_f   565.569mV/236.000ps  491.283mV/325.500ps  593.802mV/191.500ps
[Rising waveform]
R_fixture=50.000Ohm
V_fixture=1.800
V_fixture_min=1.650
V_fixture_max=1.950
0s        883.2mV    837mV      979mV
62ps      874.8mV    829.5mV    991.6mV
82ps      873.4mV    827mV      1.041V
143ps     921.4mV    829.9mV    1.417V
225ps     1.312V     931.1mV    1.766V
286ps     1.549V     1.151V     1.876V
348ps     1.685V     1.353V     1.921V
470ps     1.776V     1.557V     1.943V
633ps     1.795V     1.631V     1.948V
2ns       1.8V       1.65V      1.95V
[Rising waveform]
R_fixture=50.000Ohm
V_fixture=0
0s        58.34mV    45.54mV    79.42mV
103ps     51.68mV    42.59mV    84.2mV
205ps     77.61mV    35.51mV    301.7mV
307ps     252.6mV    54.55mV    594.6mV
409ps     471.5mV    145.6mV    835mV
572ps     769.8mV    333.3mV    1.021V
756ps     941.2mV    539.8mV    1.074V
1.083ns   1.013V     772.8mV    1.09V
1.43ns    1.024V     850.6mV    1.091V
2ns       1.026V     876.7mV    1.091V
[Falling waveform]
R_fixture=50.000Ohm
V_fixture=1.800
V_fixture_min=1.650
V_fixture_max=1.950
0s        1.8V       1.649V     1.948V
103ps     1.814V     1.651V     1.953V
205ps     1.792V     1.677V     1.738V
307ps     1.619V     1.65V      1.477V
409ps     1.422V     1.548V     1.256V
491ps     1.272V     1.451V     1.135V
593ps     1.119V     1.331V     1.056V
776ps     973.4mV    1.136V     1.008V
1.083ns   908.6mV    940.8mV    988.1mV
2ns       884.8mV    850.9mV    982.8mV
[Falling waveform]
R_fixture=50.000Ohm
V_fixture=0
0s        1.026V     882.1mV    1.094V
62ps      1.039V     890.7mV    1.064V
123ps     1.002V     906.4mV    697.5mV
184ps     702.4mV    835.1mV    383.2mV
225ps     498.5mV    696.7mV    255.5mV
286ps     287.8mV    464.5mV    157.2mV
348ps     169mV      300.5mV    114.5mV
470ps     86.66mV    129.6mV    88.2mV
633ps     64.99mV    67.06mV    81.59mV
2ns       57.41mV    44.01mV    79.27mV
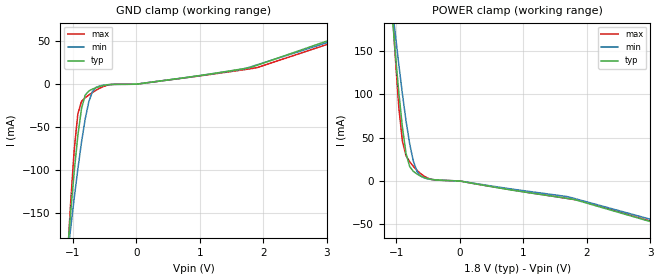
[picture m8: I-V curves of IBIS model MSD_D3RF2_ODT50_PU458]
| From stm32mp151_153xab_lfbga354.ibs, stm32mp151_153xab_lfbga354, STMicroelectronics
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[Model] MSD_D3RF2_ODT50_PU458
Model_type   Input
C_comp 2.283pF   2.245pF   2.311pF
Vinh = 1.150V
Vinl = 650.000mV
[Temperature Range]   25.000   125.000   -40.000
[Voltage Range]   1.800V   1.700V   1.900V
[GND Clamp Reference]   0.00V   0.00V   0.00V
[POWER Clamp Reference]   1.800V   1.700V   1.900V
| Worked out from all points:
|   GND clamp passes 1 mA (typ) near -0.48 V on its own axis
|   POWER clamp passes 1 mA (typ) near -0.31 V on its own axis
[GND Clamp]
-1.785V   -919.5mA   -680mA     -1.29A
-1.094V   -204.9mA   -206.2mA   -215mA
-1.036V   -151.2mA   -169.1mA   -139.7mA
-978.8mV  -102mA     -133mA     -76.77mA
-921.2mV  -59.72mA   -98.87mA   -34.62mA
-863.6mV  -28.44mA   -67.52mA   -20.13mA
-806.1mV  -12.75mA   -40.7mA    -15.8mA
-748.5mV  -7.864mA   -20.36mA   -12.6mA
-690.9mV  -5.666mA   -8.476mA   -9.634mA
-575.8mV  -2.57mA    -1.94mA    -4.54mA
1.785V    19.34mA    19.9mA     17.92mA
3.57V     64.94mA    61.75mA    60.3mA
[Power Clamp]
-1.77V    921.1mA    689.1mA    1.287A
-1.079V   202.7mA    209mA      217.6mA
-1.021V   150.4mA    171.4mA    146.4mA
-963.6mV  103mA      135mA      86.16mA
-906.1mV  62.03mA    100.5mA    45.83mA
-848.5mV  31.68mA    69.24mA    29.12mA
-790.9mV  16.58mA    42.7mA     22.2mA
-733.3mV  11.1mA     22.83mA    16.89mA
-618.2mV  5.652mA    5.708mA    8.436mA
-445.5mV  1.796mA    1.673mA    1.826mA
1.8V      -21.33mA   -20.1mA    -21.4mA
3.585V    -59.21mA   -55.81mA   -58.81mA
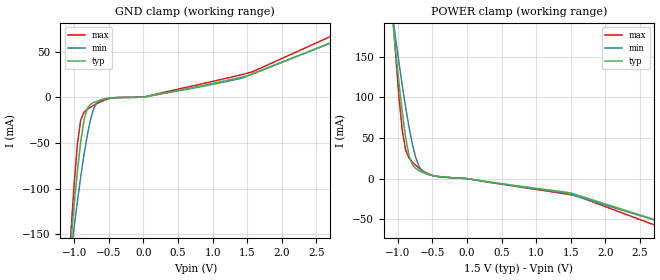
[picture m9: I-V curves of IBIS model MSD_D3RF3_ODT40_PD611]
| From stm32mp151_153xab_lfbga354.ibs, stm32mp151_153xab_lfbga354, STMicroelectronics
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[Model] MSD_D3RF3_ODT40_PD611
Model_type   Input
C_comp 2.331pF   2.289pF   2.408pF
Vinh = 925.000mV
Vinl = 575.000mV
[Temperature Range]   25.000   125.000   -40.000
[Voltage Range]   1.500V   1.425V   1.575V
[GND Clamp Reference]   0.00V   0.00V   0.00V
[POWER Clamp Reference]   1.500V   1.425V   1.575V
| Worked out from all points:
|   GND clamp passes 1 mA (typ) near -0.48 V on its own axis
|   POWER clamp passes 1 mA (typ) near -0.21 V on its own axis
[GND Clamp]
-1.48V    -589.9mA   -457.5mA   -789mA
-1.05V    -159.5mA   -171.9mA   -149.7mA
-1.002V   -118.1mA   -142.3mA   -95.25mA
-954.6mV  -80.66mA   -114mA     -51.17mA
-906.8mV  -48.75mA   -87.22mA   -24.91mA
-859.1mV  -25.02mA   -62.77mA   -16.22mA
-763.6mV  -7.644mA   -23.91mA   -10.84mA
-715.9mV  -5.7mA     -11.93mA   -8.73mA
-620.5mV  -3.242mA   -2.968mA   -5mA
900nV     14.36nA    13.21nA    16.86nA
1.575V    25.54mA    25.37mA    27.81mA
2.959V    67.24mA    66.9mA     75.2mA
[Power Clamp]
-1.459V   583.4mA    459mA      772.8mA
-1.077V   197.9mA    201.6mA    208.3mA
-1.03V    155.5mA    171.1mA    150.2mA
-981.8mV  116.1mA    141.6mA    98.4mA
-934.1mV  80.58mA    113.5mA    58.12mA
-886.4mV  50.22mA    87.22mA    34.86mA
-838.6mV  28.3mA     63.41mA    25.28mA
-790.9mV  17.12mA    42.77mA    20.4mA
-695.5mV  9.87mA     15.25mA    13.06mA
-504.6mV  3.782mA    3.871mA    3.969mA
1.548V    -19.02mA   -20.84mA   -20.65mA
2.98V     -57.9mA    -58.16mA   -65.76mA
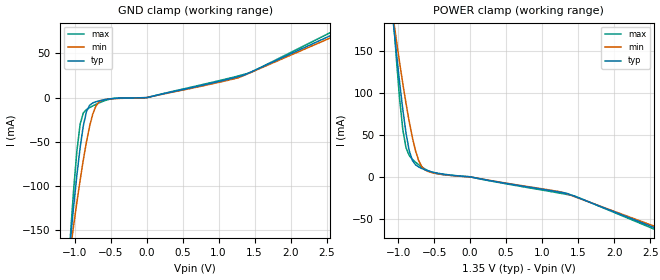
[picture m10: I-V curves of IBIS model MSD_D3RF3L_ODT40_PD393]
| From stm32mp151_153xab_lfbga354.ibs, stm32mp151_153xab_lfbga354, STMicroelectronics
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[Model] MSD_D3RF3L_ODT40_PD393
Model_type   Input
C_comp 2.300pF   2.261pF   2.351pF
Vinh = 810.000mV
Vinl = 540.000mV
[Model Spec]
Vinh   810.000mV   777.000mV   860.000mV
Vinl   540.000mV   507.000mV   590.000mV
[Temperature Range]   25.000   125.000   -40.000
[Voltage Range]   1.350V   1.283V   1.450V
[GND Clamp Reference]   0.00V   0.00V   0.00V
[POWER Clamp Reference]   1.350V   1.283V   1.450V
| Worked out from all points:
|   GND clamp passes 1 mA (typ) near -0.47 V on its own axis
|   POWER clamp passes 1 mA (typ) near -0.15 V on its own axis
[GND Clamp]
-1.318V   -415.2mA   -341.2mA   -533mA
-1.055V   -159.1mA   -170.4mA   -153.1mA
-1.011V   -121.6mA   -143.6mA   -102.4mA
-966.7mV  -87.05mA   -117.8mA   -59.67mA
-922.7mV  -56.63mA   -93.44mA   -30.03mA
-878.8mV  -31.97mA   -70.64mA   -17.39mA
-834.9mV  -15.85mA   -50.08mA   -13.44mA
-747mV    -5.938mA   -18.5mA    -9.346mA
-615.1mV  -2.796mA   -2.814mA   -4.422mA
200nV     3.955nA    3.699nA    4.154nA
1.45V     29.08mA    28.61mA    28.64mA
2.68V     74.89mA    72.12mA    78.81mA
[Power Clamp]
-1.33V    440.5mA    363.1mA    565.5mA
-1.067V   184.7mA    189.9mA    192.1mA
-1.023V   147.6mA    162.7mA    139.9mA
-978.8mV  112.6mA    136.5mA    93.18mA
-934.9mV  80.54mA    111.5mA    56.4mA
-890.9mV  52.67mA    88.09mA    34.99mA
-847mV    31.61mA    66.6mA     25.71mA
-759.1mV  14.5mA     31.41mA    17.58mA
-671.2mV  10.01mA    12.09mA    11.74mA
-583.3mV  7.115mA    6.322mA    7.313mA
1.438V    -22.93mA   -23.33mA   -22.63mA
2.668V    -64.54mA   -62.64mA   -66.69mA
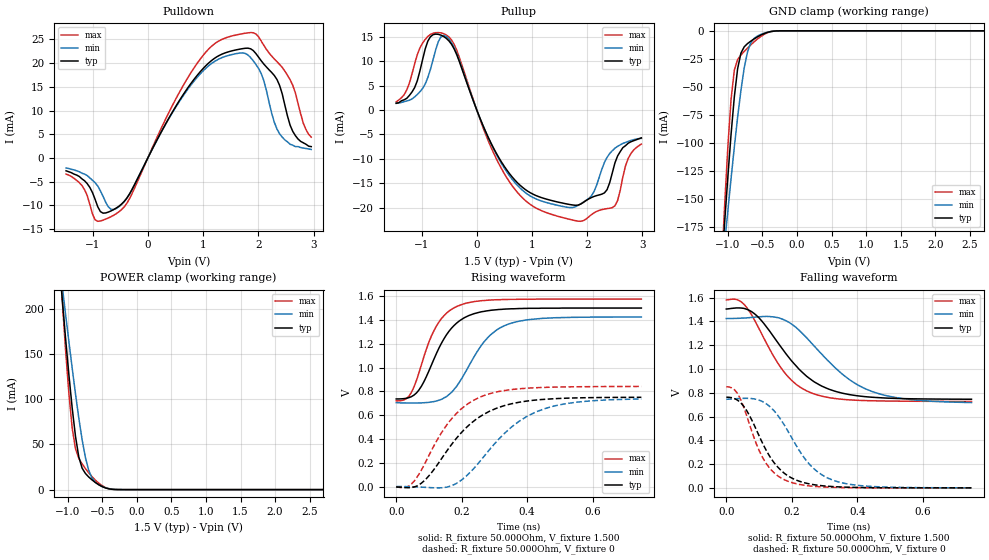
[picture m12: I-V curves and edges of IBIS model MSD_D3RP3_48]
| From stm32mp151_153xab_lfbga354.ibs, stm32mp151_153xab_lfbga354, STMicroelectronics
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[Model] MSD_D3RP3_48
Model_type   I/O
C_comp 2.233pF   2.153pF   2.350pF
Vinh = 925.000mV
Vinl = 575.000mV
Vmeas = 750.000mV
Vref = 750.000mV
[Model Spec]
Vinh   925.000mV   888.000mV   963.000mV
Vinl   575.000mV   538.000mV   613.000mV
Vmeas   750.000mV   713.000mV   788.000mV
Vref   750.000mV   713.000mV   788.000mV
[Temperature Range]   25.000   125.000   -40.000
[Voltage Range]   1.500V   1.425V   1.575V
[GND Clamp Reference]   0.00V   0.00V   0.00V
[Pulldown Reference]   0.00V   0.00V   0.00V
[POWER Clamp Reference]   1.500V   1.425V   1.575V
[Pullup Reference]   1.500V   1.425V   1.575V
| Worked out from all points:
|   slope of the pulldown table from 0 to 0.225 V, typ, clamps not added: 44.1 ohm
|   slope of the pullup table from 0 to 0.225 V, typ, clamps not added: 37.5 ohm
|   GND clamp passes 1 mA (typ) near -0.40 V on its own axis
|   POWER clamp passes 1 mA (typ) near -0.41 V on its own axis
|   rising waveform, R_fixture 50.000Ohm, V_fixture 1.500: 20-80 % time 88.6ps typ, 105ps min, 74.5ps max; typ from 0.736 V to 1.5 V
|   rising waveform, R_fixture 50.000Ohm, V_fixture 0: 20-80 % time 147ps typ, 163ps min, 126ps max; typ from -0.003 V to 0.75 V
|   falling waveform, R_fixture 50.000Ohm, V_fixture 1.500: 20-80 % time 143ps typ, 168ps min, 116ps max; typ from 1.5 V to 0.745 V
|   falling waveform, R_fixture 50.000Ohm, V_fixture 0: 20-80 % time 94.7ps typ, 112ps min, 78.3ps max; typ from 0.762 V to 0 V
[GND Clamp]
-1.48V    -592.8mA   -479.1mA   -761.2mA
-1.098V   -217.8mA   -223.1mA   -219.7mA
-1.05V    -173.8mA   -192.1mA   -159.3mA
-1.002V   -131.7mA   -161.7mA   -105mA
-954.6mV  -92.68mA   -132.2mA   -61.41mA
-906.8mV  -58.93mA   -103.8mA   -35.09mA
-859.1mV  -33.75mA   -77.07mA   -25.6mA
-811.4mV  -19.88mA   -53.01mA   -21.59mA
-715.9mV  -11.39mA   -18.72mA   -15.38mA
-572.7mV  -5.408mA   -4.63mA    -7.309mA
-286.4mV  -67.53uA   -115uA     -52.79uA
2.959V    27.81nA    447.4nA    3.164nA
[Power Clamp]
-1.459V   573.5mA    476.8mA    715.7mA
-1.077V   209.6mA    224.3mA    208.4mA
-1.03V    167.1mA    193.7mA    154.3mA
-981.8mV  126.8mA    163.5mA    105.9mA
-934.1mV  89.99mA    134.1mA    67.88mA
-886.4mV  58.74mA    105.7mA    45.04mA
-838.6mV  36.05mA    79.08mA    34.56mA
-743.2mV  17.84mA    35.43mA    23.27mA
-647.7mV  10.73mA    12.81mA    14.31mA
-552.3mV  5.47mA     5.422mA    7.21mA
-313.6mV  99.22uA    231.1uA    112.6uA
2.98V     -43.92nA   -827nA     -4.18nA
[Pulldown]
-1.48V    -2.7mA     -2.1mA     -3.4mA
-1.193V   -4.4mA     -3.2mA     -5.8mA
-954.6mV  -8.72mA    -5.2mA     -13.02mA
-811.4mV  -11.63mA   -8.06mA    -13.11mA
-525mV    -10.19mA   -10.28mA   -11.37mA
906.8mV   17.61mA    17.19mA    20.18mA
1.241V    21.28mA    20.59mA    24.36mA
1.766V    23.15mA    22.04mA    26.32mA
2.052V    20.52mA    17.84mA    24.69mA
2.386V    15.31mA    5.1mA      19.73mA
2.625V    5.6mA      2.7mA      15.3mA
2.959V    2.4mA      1.8mA      4.4mA
[Pullup]
-1.459V   1.4mA      1.357mA    1.671mA
-1.125V   4.6mA      2.686mA    9.5mA
-934.1mV  12.51mA    5.329mA    14.46mA
-695.5mV  15.51mA    14.04mA    15.87mA
-552.3mV  14.69mA    15.08mA    15.38mA
640.9mV   -13.71mA   -14.18mA   -15.51mA
1.834V    -19.47mA   -19.54mA   -22.76mA
2.12V     -17.71mA   -16.77mA   -21.07mA
2.311V    -16.97mA   -10.74mA   -20.28mA
2.502V    -10.8mA    -7.814mA   -19.6mA
2.741V    -6.8mA     -6.429mA   -9.928mA
2.98V     -5.7mA     -5.8mA     -6.971mA
[Ramp]
R_load=50.000Ohm
dV/dt_r   452.310mV/118.500ps  436.319mV/135.500ps  507.240mV/101.000ps
dV/dt_f   452.310mV/118.500ps  436.319mV/141.500ps  507.240mV/97.500ps
[Rising waveform]
R_fixture=50.000Ohm
V_fixture=1.500
V_fixture_min=1.425
V_fixture_max=1.575
0s        736.1mV    704.2mV    719.9mV
39ps      747.3mV    702.1mV    759.3mV
69ps      809.7mV    702.5mV    951.9mV
100ps     972.3mV    707.5mV    1.215V
123ps     1.119V     719.3mV    1.349V
184ps     1.372V     840.4mV    1.512V
268ps     1.472V     1.215V     1.563V
337ps     1.492V     1.359V     1.572V
444ps     1.499V     1.413V     1.575V
749ps     1.5V       1.425V     1.575V
[Rising waveform]
R_fixture=50.000Ohm
V_fixture=0
0s        -3.334mV   657.3uV    -4.083mV
39ps      -9.649mV   -963.6uV   4.42mV
77ps      28.49mV    -4.894mV   138.7mV
161ps     323.3mV    244.5uV    541.3mV
199ps     452.7mV    53.39mV    652.9mV
253ps     582.2mV    202.4mV    747.8mV
353ps     696.1mV    501.6mV    815.5mV
429ps     727.6mV    629.2mV    830.7mV
552ps     745mV      709.2mV    838.5mV
749ps     750mV      735.3mV    841.4mV
[Falling waveform]
R_fixture=50.000Ohm
V_fixture=1.500
V_fixture_min=1.425
V_fixture_max=1.575
0s        1.504V     1.424V     1.58V
46ps      1.512V     1.427V     1.563V
92ps      1.45V      1.437V     1.38V
177ps     1.147V     1.412V     972.8mV
215ps     1.02V      1.344V     866.6mV
253ps     922.3mV    1.239V     806.2mV
353ps     797.1mV    959.3mV    744.9mV
444ps     762.2mV    811.6mV    732.4mV
559ps     749.4mV    743.6mV    728.6mV
749ps     745.2mV    717.3mV    726.7mV
[Falling waveform]
R_fixture=50.000Ohm
V_fixture=0
0s        762.3mV    744.6mV    850.2mV
39ps      727.5mV    751mV      769.8mV
69ps      617mV      752.2mV    549.5mV
108ps     390.9mV    728.9mV    270mV
138ps     241.6mV    669.5mV    148mV
184ps     108.9mV    496.7mV    60.22mV
253ps     33.86mV    201.8mV    16.81mV
330ps     10.06mV    60.56mV    4.185mV
444ps     1.789mV    11.92mV    606.6uV
749ps     37.23uV    300.4uV    21.3uV
